VERSION 5.7 ;
  NOWIREEXTENSIONATPIN ON ;
  DIVIDERCHAR "/" ;
  BUSBITCHARS "[]" ;
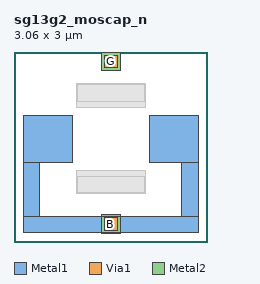
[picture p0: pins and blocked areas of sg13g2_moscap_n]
MACRO sg13g2_moscap_n
  CLASS BLOCK ;
  FOREIGN sg13g2_moscap_n ;
  ORIGIN 0.980 1.130 ;
  SIZE 3.060 BY 3.000 ;
  PIN G
    PORT
      LAYER Metal1 ;
        RECT 0.400 1.570 0.700 1.870 ;
      LAYER Via1 ;
        RECT 0.450 1.620 0.650 1.820 ;
      LAYER Metal2 ;
        RECT 0.400 1.570 0.700 1.870 ;
    END
  END G
  PIN B
    ANTENNADIFFAREA 2.540000 ;
    PORT
      LAYER Metal1 ;
        RECT -0.830 0.130 -0.060 0.870 ;
        RECT 1.160 0.130 1.930 0.870 ;
        RECT -0.830 -0.720 -0.570 0.130 ;
        RECT 0.400 -0.720 0.700 -0.700 ;
        RECT 1.670 -0.720 1.930 0.130 ;
        RECT -0.830 -0.980 1.930 -0.720 ;
        RECT 0.400 -1.000 0.700 -0.980 ;
      LAYER Via1 ;
        RECT 0.450 -0.950 0.650 -0.750 ;
      LAYER Metal2 ;
        RECT 0.400 -1.000 0.700 -0.700 ;
    END
  END B
  OBS
      LAYER GatPoly ;
        RECT 0.000 1.000 1.100 1.370 ;
        RECT 0.000 -0.370 1.100 0.000 ;
      LAYER Metal1 ;
        RECT 0.020 1.090 1.080 1.350 ;
        RECT 0.020 -0.350 1.080 -0.090 ;
  END
END sg13g2_moscap_n
END LIBRARY

